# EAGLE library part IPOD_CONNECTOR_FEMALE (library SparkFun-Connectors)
iPod Female Connector This is the connector found inside current iPods. Use this connector to attach to iPod accessories like Nike+iPods, etc. Schematic and footprint are not yet production proven. Spark Fun Electronics SKU : DEV-08035

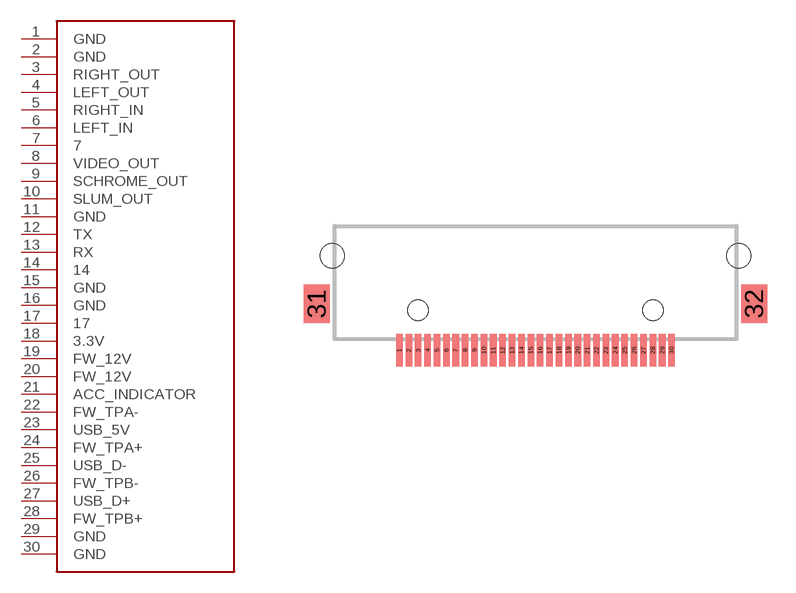
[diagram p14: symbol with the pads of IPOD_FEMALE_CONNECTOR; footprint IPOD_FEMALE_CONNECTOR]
Designator prefix -

## IPOD_CONNECTOR_FEMALE  [IPOD_FEMALE_CONNECTOR]
1  GND
2  GND
3  RIGHT_OUT
4  LEFT_OUT
5  RIGHT_IN
6  LEFT_IN
7  7
8  VIDEO_OUT
9  SCHROME_OUT
10  SLUM_OUT
11  GND
12  TX
13  RX
14  14
15  GND
16  GND
17  17
18  3.3V
19  FW_12V
20  FW_12V
21  ACC_INDICATOR
22  FW_TPA-
23  USB_5V
24  FW_TPA+
25  USB_D-
26  FW_TPB-
27  USB_D+
28  FW_TPB+
29  GND
30  GND

## Footprint IPOD_FEMALE_CONNECTOR (pad centres in mm)
smd 0.35 x 1.75: 1 -7.25,0; 2 -6.75,0; 3 -6.25,0; 4 -5.75,0; 5 -5.25,0; 6 -4.75,0; 7 -4.25,0; 8 -3.75,0; 9 -3.25,0; 10 -2.75,0; 11 -2.25,0; 12 -1.75,0; 13 -1.25,0; 14 -0.75,0; 15 -0.25,0; 16 0.25,0; 17 0.75,0; 18 1.25,0; 19 1.75,0; 20 2.25,0; 21 2.75,0; 22 3.25,0; 23 3.75,0; 24 4.25,0; 25 4.75,0; 26 5.25,0; 27 5.75,0; 28 6.25,0; 29 6.75,0; 30 7.25,0
smd 1.4 x 2.05: 31 -11.65,2.475; 32 11.65,2.475
hole 1.1 at 6.25,2.125
hole 1.1 at -6.25,2.125
hole 1.3 at 10.825,5.025
hole 1.3 at -10.825,5.025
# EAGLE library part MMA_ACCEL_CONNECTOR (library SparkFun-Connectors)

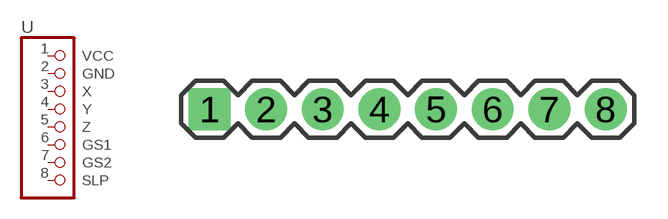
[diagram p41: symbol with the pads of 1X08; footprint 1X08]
Designator prefix -

## MMA_ACCEL_CONNECTOR  [1X08]
1  VCC  pas
2  GND  pas
3  X  pas
4  Y  pas
5  Z  pas
6  GS1  pas
7  GS2  pas
8  SLP  pas

## Footprint 1X08 (pad centres in mm)
drill 1.016 pad 1.88 square: 1 0,0
drill 1.016 pad 1.88: 2 2.54,0; 3 5.08,0; 4 7.62,0; 5 10.16,0; 6 12.7,0; 7 15.24,0; 8 17.78,0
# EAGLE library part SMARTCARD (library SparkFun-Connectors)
Smart card socket- PRT-09368

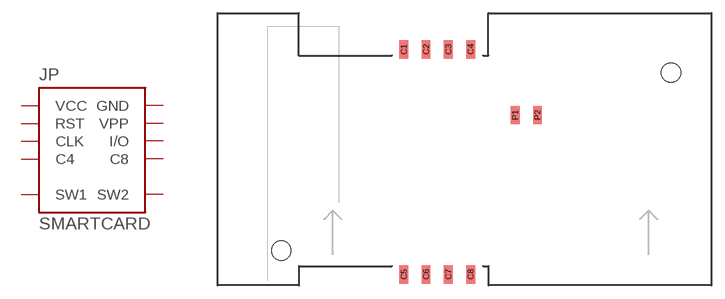
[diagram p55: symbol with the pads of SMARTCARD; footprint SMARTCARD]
Designator prefix JP

## SMARTCARDSMD  [SMARTCARD]
C1  VCC
C2  RST
C3  CLK
C4  C4
C5  GND
C6  VPP
C7  I/O
C8  C8
P1  SW1
P2  SW2

## Footprint SMARTCARD (pad centres in mm)
Description: S..m..r..t. I am so smrt!
smd 1 x 2.1: C1 -6.92,11.4; C2 -4.38,11.4; C3 -1.84,11.4; C4 0.7,11.4; C5 -6.92,-14.3; C6 -4.38,-14.3; C7 -1.84,-14.3; C8 0.7,-14.3; P1 5.78,3.91; P2 8.32,3.91
hole 2.2 at 23.56,8.75
hole 2.2 at -20.89,-11.57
